VERSION 5.8 ;
BUSBITCHARS "[]" ;
DIVIDERCHAR "/" ;
UNITS
    DATABASE MICRONS 1000 ;
END UNITS

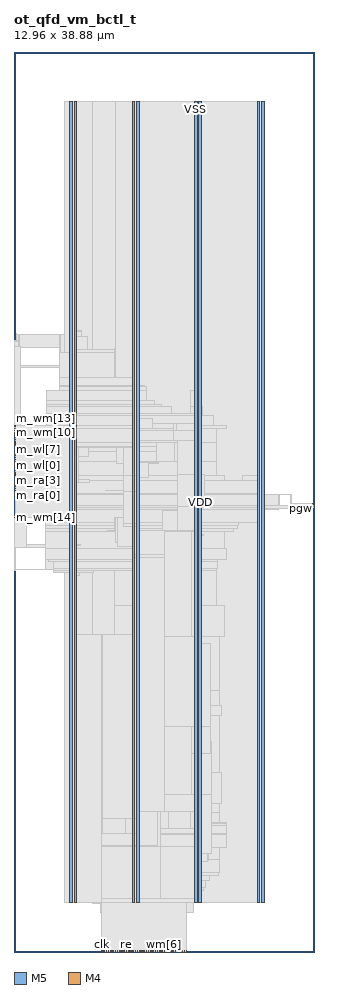
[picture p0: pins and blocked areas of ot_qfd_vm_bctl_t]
MACRO ot_qfd_vm_bctl_t
  FOREIGN ot_qfd_vm_bctl_t 0 0 ;
  CLASS BLOCK ;
  SIZE 12.96 BY 38.88 ;
  PIN clk
    DIRECTION INPUT ;
    USE SIGNAL ;
    PORT
      LAYER M5 ;
        RECT  3.792 0 3.816 0.084 ;
    END
  END clk
  PIN m_ra[0]
    DIRECTION OUTPUT ;
    USE SIGNAL ;
    PORT
      LAYER M4 ;
        RECT  0 19.728 0.084 19.752 ;
    END
  END m_ra[0]
  PIN m_ra[1]
    DIRECTION OUTPUT ;
    USE SIGNAL ;
    PORT
      LAYER M4 ;
        RECT  0 19.824 0.084 19.848 ;
    END
  END m_ra[1]
  PIN m_ra[2]
    DIRECTION OUTPUT ;
    USE SIGNAL ;
    PORT
      LAYER M4 ;
        RECT  0 19.92 0.084 19.944 ;
    END
  END m_ra[2]
  PIN m_ra[3]
    DIRECTION OUTPUT ;
    USE SIGNAL ;
    PORT
      LAYER M4 ;
        RECT  0 20.016 0.084 20.04 ;
    END
  END m_ra[3]
  PIN m_ra[4]
    DIRECTION OUTPUT ;
    USE SIGNAL ;
    PORT
      LAYER M4 ;
        RECT  0 20.112 0.084 20.136 ;
    END
  END m_ra[4]
  PIN m_ra[5]
    DIRECTION OUTPUT ;
    USE SIGNAL ;
    PORT
      LAYER M4 ;
        RECT  0 20.208 0.084 20.232 ;
    END
  END m_ra[5]
  PIN m_ra[6]
    DIRECTION OUTPUT ;
    USE SIGNAL ;
    PORT
      LAYER M4 ;
        RECT  0 20.304 0.084 20.328 ;
    END
  END m_ra[6]
  PIN m_ra[7]
    DIRECTION OUTPUT ;
    USE SIGNAL ;
    PORT
      LAYER M4 ;
        RECT  0 20.4 0.084 20.424 ;
    END
  END m_ra[7]
  PIN m_re
    DIRECTION OUTPUT ;
    USE SIGNAL ;
    PORT
      LAYER M4 ;
        RECT  0 20.496 0.084 20.52 ;
    END
  END m_re
  PIN m_we
    DIRECTION OUTPUT ;
    USE SIGNAL ;
    PORT
      LAYER M4 ;
        RECT  0 20.592 0.084 20.616 ;
    END
  END m_we
  PIN m_wl[0]
    DIRECTION OUTPUT ;
    USE SIGNAL ;
    PORT
      LAYER M4 ;
        RECT  0 20.688 0.084 20.712 ;
    END
  END m_wl[0]
  PIN m_wl[1]
    DIRECTION OUTPUT ;
    USE SIGNAL ;
    PORT
      LAYER M4 ;
        RECT  0 20.784 0.084 20.808 ;
    END
  END m_wl[1]
  PIN m_wl[2]
    DIRECTION OUTPUT ;
    USE SIGNAL ;
    PORT
      LAYER M4 ;
        RECT  0 20.88 0.084 20.904 ;
    END
  END m_wl[2]
  PIN m_wl[3]
    DIRECTION OUTPUT ;
    USE SIGNAL ;
    PORT
      LAYER M4 ;
        RECT  0 20.976 0.084 21 ;
    END
  END m_wl[3]
  PIN m_wl[4]
    DIRECTION OUTPUT ;
    USE SIGNAL ;
    PORT
      LAYER M4 ;
        RECT  0 21.072 0.084 21.096 ;
    END
  END m_wl[4]
  PIN m_wl[5]
    DIRECTION OUTPUT ;
    USE SIGNAL ;
    PORT
      LAYER M4 ;
        RECT  0 21.168 0.084 21.192 ;
    END
  END m_wl[5]
  PIN m_wl[6]
    DIRECTION OUTPUT ;
    USE SIGNAL ;
    PORT
      LAYER M4 ;
        RECT  0 21.264 0.084 21.288 ;
    END
  END m_wl[6]
  PIN m_wl[7]
    DIRECTION OUTPUT ;
    USE SIGNAL ;
    PORT
      LAYER M4 ;
        RECT  0 21.36 0.084 21.384 ;
    END
  END m_wl[7]
  PIN m_wm[0]
    DIRECTION OUTPUT ;
    USE SIGNAL ;
    PORT
      LAYER M4 ;
        RECT  0 21.456 0.084 21.48 ;
    END
  END m_wm[0]
  PIN m_wm[10]
    DIRECTION OUTPUT ;
    USE SIGNAL ;
    PORT
      LAYER M4 ;
        RECT  0 22.416 0.084 22.44 ;
    END
  END m_wm[10]
  PIN m_wm[11]
    DIRECTION OUTPUT ;
    USE SIGNAL ;
    PORT
      LAYER M4 ;
        RECT  0 22.512 0.084 22.536 ;
    END
  END m_wm[11]
  PIN m_wm[12]
    DIRECTION OUTPUT ;
    USE SIGNAL ;
    PORT
      LAYER M4 ;
        RECT  0 22.608 0.084 22.632 ;
    END
  END m_wm[12]
  PIN m_wm[13]
    DIRECTION OUTPUT ;
    USE SIGNAL ;
    PORT
      LAYER M4 ;
        RECT  0 22.704 0.084 22.728 ;
    END
  END m_wm[13]
  PIN m_wm[14]
    DIRECTION OUTPUT ;
    USE SIGNAL ;
    PORT
      LAYER M4 ;
        RECT  0 18.768 0.084 18.792 ;
    END
  END m_wm[14]
  PIN m_wm[15]
    DIRECTION OUTPUT ;
    USE SIGNAL ;
    PORT
      LAYER M4 ;
        RECT  0 18.864 0.084 18.888 ;
    END
  END m_wm[15]
  PIN m_wm[1]
    DIRECTION OUTPUT ;
    USE SIGNAL ;
    PORT
      LAYER M4 ;
        RECT  0 21.552 0.084 21.576 ;
    END
  END m_wm[1]
  PIN m_wm[2]
    DIRECTION OUTPUT ;
    USE SIGNAL ;
    PORT
      LAYER M4 ;
        RECT  0 21.648 0.084 21.672 ;
    END
  END m_wm[2]
  PIN m_wm[3]
    DIRECTION OUTPUT ;
    USE SIGNAL ;
    PORT
      LAYER M4 ;
        RECT  0 21.744 0.084 21.768 ;
    END
  END m_wm[3]
  PIN m_wm[4]
    DIRECTION OUTPUT ;
    USE SIGNAL ;
    PORT
      LAYER M4 ;
        RECT  0 21.84 0.084 21.864 ;
    END
  END m_wm[4]
  PIN m_wm[5]
    DIRECTION OUTPUT ;
    USE SIGNAL ;
    PORT
      LAYER M4 ;
        RECT  0 21.936 0.084 21.96 ;
    END
  END m_wm[5]
  PIN m_wm[6]
    DIRECTION OUTPUT ;
    USE SIGNAL ;
    PORT
      LAYER M4 ;
        RECT  0 22.032 0.084 22.056 ;
    END
  END m_wm[6]
  PIN m_wm[7]
    DIRECTION OUTPUT ;
    USE SIGNAL ;
    PORT
      LAYER M4 ;
        RECT  0 22.128 0.084 22.152 ;
    END
  END m_wm[7]
  PIN m_wm[8]
    DIRECTION OUTPUT ;
    USE SIGNAL ;
    PORT
      LAYER M4 ;
        RECT  0 22.224 0.084 22.248 ;
    END
  END m_wm[8]
  PIN m_wm[9]
    DIRECTION OUTPUT ;
    USE SIGNAL ;
    PORT
      LAYER M4 ;
        RECT  0 22.32 0.084 22.344 ;
    END
  END m_wm[9]
  PIN me_in
    DIRECTION INPUT ;
    USE SIGNAL ;
    PORT
      LAYER M5 ;
        RECT  3.888 0 3.912 0.084 ;
    END
  END me_in
  PIN pgw
    DIRECTION OUTPUT ;
    USE SIGNAL ;
    PORT
      LAYER M4 ;
        RECT  12.876 19.152 12.96 19.176 ;
    END
  END pgw
  PIN pop
    DIRECTION INPUT ;
    USE SIGNAL ;
    PORT
      LAYER M5 ;
        RECT  3.984 0 4.008 0.084 ;
    END
  END pop
  PIN ra[0]
    DIRECTION INPUT ;
    USE SIGNAL ;
    PORT
      LAYER M5 ;
        RECT  4.08 0 4.104 0.084 ;
    END
  END ra[0]
  PIN ra[1]
    DIRECTION INPUT ;
    USE SIGNAL ;
    PORT
      LAYER M5 ;
        RECT  4.176 0 4.2 0.084 ;
    END
  END ra[1]
  PIN ra[2]
    DIRECTION INPUT ;
    USE SIGNAL ;
    PORT
      LAYER M5 ;
        RECT  4.272 0 4.296 0.084 ;
    END
  END ra[2]
  PIN ra[3]
    DIRECTION INPUT ;
    USE SIGNAL ;
    PORT
      LAYER M5 ;
        RECT  4.368 0 4.392 0.084 ;
    END
  END ra[3]
  PIN ra[4]
    DIRECTION INPUT ;
    USE SIGNAL ;
    PORT
      LAYER M5 ;
        RECT  4.464 0 4.488 0.084 ;
    END
  END ra[4]
  PIN ra[5]
    DIRECTION INPUT ;
    USE SIGNAL ;
    PORT
      LAYER M5 ;
        RECT  4.56 0 4.584 0.084 ;
    END
  END ra[5]
  PIN ra[6]
    DIRECTION INPUT ;
    USE SIGNAL ;
    PORT
      LAYER M5 ;
        RECT  4.656 0 4.68 0.084 ;
    END
  END ra[6]
  PIN ra[7]
    DIRECTION INPUT ;
    USE SIGNAL ;
    PORT
      LAYER M5 ;
        RECT  4.752 0 4.776 0.084 ;
    END
  END ra[7]
  PIN re
    DIRECTION INPUT ;
    USE SIGNAL ;
    PORT
      LAYER M5 ;
        RECT  4.848 0 4.872 0.084 ;
    END
  END re
  PIN rst_n
    DIRECTION INPUT ;
    USE SIGNAL ;
    PORT
      LAYER M5 ;
        RECT  4.944 0 4.968 0.084 ;
    END
  END rst_n
  PIN rtg
    DIRECTION OUTPUT ;
    USE SIGNAL ;
    PORT
      LAYER M4 ;
        RECT  12.876 19.248 12.96 19.272 ;
    END
  END rtg
  PIN we
    DIRECTION INPUT ;
    USE SIGNAL ;
    PORT
      LAYER M5 ;
        RECT  5.04 0 5.064 0.084 ;
    END
  END we
  PIN wl[0]
    DIRECTION INPUT ;
    USE SIGNAL ;
    PORT
      LAYER M5 ;
        RECT  5.136 0 5.16 0.084 ;
    END
  END wl[0]
  PIN wl[1]
    DIRECTION INPUT ;
    USE SIGNAL ;
    PORT
      LAYER M5 ;
        RECT  5.232 0 5.256 0.084 ;
    END
  END wl[1]
  PIN wl[2]
    DIRECTION INPUT ;
    USE SIGNAL ;
    PORT
      LAYER M5 ;
        RECT  5.328 0 5.352 0.084 ;
    END
  END wl[2]
  PIN wl[3]
    DIRECTION INPUT ;
    USE SIGNAL ;
    PORT
      LAYER M5 ;
        RECT  5.424 0 5.448 0.084 ;
    END
  END wl[3]
  PIN wl[4]
    DIRECTION INPUT ;
    USE SIGNAL ;
    PORT
      LAYER M5 ;
        RECT  5.52 0 5.544 0.084 ;
    END
  END wl[4]
  PIN wl[5]
    DIRECTION INPUT ;
    USE SIGNAL ;
    PORT
      LAYER M5 ;
        RECT  5.616 0 5.64 0.084 ;
    END
  END wl[5]
  PIN wl[6]
    DIRECTION INPUT ;
    USE SIGNAL ;
    PORT
      LAYER M5 ;
        RECT  5.712 0 5.736 0.084 ;
    END
  END wl[6]
  PIN wl[7]
    DIRECTION INPUT ;
    USE SIGNAL ;
    PORT
      LAYER M5 ;
        RECT  5.808 0 5.832 0.084 ;
    END
  END wl[7]
  PIN wm[0]
    DIRECTION INPUT ;
    USE SIGNAL ;
    PORT
      LAYER M5 ;
        RECT  5.904 0 5.928 0.084 ;
    END
  END wm[0]
  PIN wm[10]
    DIRECTION INPUT ;
    USE SIGNAL ;
    PORT
      LAYER M5 ;
        RECT  6.864 0 6.888 0.084 ;
    END
  END wm[10]
  PIN wm[11]
    DIRECTION INPUT ;
    USE SIGNAL ;
    PORT
      LAYER M5 ;
        RECT  6.96 0 6.984 0.084 ;
    END
  END wm[11]
  PIN wm[12]
    DIRECTION INPUT ;
    USE SIGNAL ;
    PORT
      LAYER M5 ;
        RECT  7.056 0 7.08 0.084 ;
    END
  END wm[12]
  PIN wm[13]
    DIRECTION INPUT ;
    USE SIGNAL ;
    PORT
      LAYER M5 ;
        RECT  7.152 0 7.176 0.084 ;
    END
  END wm[13]
  PIN wm[14]
    DIRECTION INPUT ;
    USE SIGNAL ;
    PORT
      LAYER M5 ;
        RECT  7.248 0 7.272 0.084 ;
    END
  END wm[14]
  PIN wm[15]
    DIRECTION INPUT ;
    USE SIGNAL ;
    PORT
      LAYER M5 ;
        RECT  7.344 0 7.368 0.084 ;
    END
  END wm[15]
  PIN wm[1]
    DIRECTION INPUT ;
    USE SIGNAL ;
    PORT
      LAYER M5 ;
        RECT  6 0 6.024 0.084 ;
    END
  END wm[1]
  PIN wm[2]
    DIRECTION INPUT ;
    USE SIGNAL ;
    PORT
      LAYER M5 ;
        RECT  6.096 0 6.12 0.084 ;
    END
  END wm[2]
  PIN wm[3]
    DIRECTION INPUT ;
    USE SIGNAL ;
    PORT
      LAYER M5 ;
        RECT  6.192 0 6.216 0.084 ;
    END
  END wm[3]
  PIN wm[4]
    DIRECTION INPUT ;
    USE SIGNAL ;
    PORT
      LAYER M5 ;
        RECT  6.288 0 6.312 0.084 ;
    END
  END wm[4]
  PIN wm[5]
    DIRECTION INPUT ;
    USE SIGNAL ;
    PORT
      LAYER M5 ;
        RECT  6.384 0 6.408 0.084 ;
    END
  END wm[5]
  PIN wm[6]
    DIRECTION INPUT ;
    USE SIGNAL ;
    PORT
      LAYER M5 ;
        RECT  6.48 0 6.504 0.084 ;
    END
  END wm[6]
  PIN wm[7]
    DIRECTION INPUT ;
    USE SIGNAL ;
    PORT
      LAYER M5 ;
        RECT  6.576 0 6.6 0.084 ;
    END
  END wm[7]
  PIN wm[8]
    DIRECTION INPUT ;
    USE SIGNAL ;
    PORT
      LAYER M5 ;
        RECT  6.672 0 6.696 0.084 ;
    END
  END wm[8]
  PIN wm[9]
    DIRECTION INPUT ;
    USE SIGNAL ;
    PORT
      LAYER M5 ;
        RECT  6.768 0 6.792 0.084 ;
    END
  END wm[9]
  PIN xg
    DIRECTION OUTPUT ;
    USE SIGNAL ;
    PORT
      LAYER M4 ;
        RECT  12.876 19.344 12.96 19.368 ;
    END
  END xg
  PIN xv
    DIRECTION INPUT ;
    USE SIGNAL ;
    PORT
      LAYER M5 ;
        RECT  7.44 0 7.464 0.084 ;
    END
  END xv
  PIN VDD
    DIRECTION INOUT ;
    USE POWER ;
    PORT
      LAYER M5 ;
        RECT  10.692 2.151 10.812 36.729 ;
        RECT  7.992 2.151 8.112 36.729 ;
        RECT  5.292 2.151 5.412 36.729 ;
        RECT  2.592 2.151 2.712 36.729 ;
    END
  END VDD
  PIN VSS
    DIRECTION INOUT ;
    USE GROUND ;
    PORT
      LAYER M5 ;
        RECT  10.5 2.137 10.62 36.743 ;
        RECT  7.8 2.137 7.92 36.743 ;
        RECT  5.1 2.137 5.22 36.743 ;
        RECT  2.4 2.137 2.52 36.743 ;
    END
  END VSS
  # OT_OBS_CLOSED layer=M5 d_um=1.536 added=14
  OBS
    LAYER RVTN ;
     RECT  2.16 2.16 10.8 2.295 ;
     RECT  2.16 2.565 10.8 2.835 ;
     RECT  2.16 3.105 10.8 3.375 ;
     RECT  2.16 3.645 10.8 3.915 ;
     RECT  2.16 4.185 10.8 4.455 ;
     RECT  2.16 4.725 10.8 4.995 ;
     RECT  2.16 5.265 10.8 5.535 ;
     RECT  2.16 5.805 10.8 6.075 ;
     RECT  2.16 6.345 10.8 6.615 ;
     RECT  2.16 6.885 10.8 7.155 ;
     RECT  2.16 7.425 10.8 7.695 ;
     RECT  2.16 7.965 10.8 8.235 ;
     RECT  2.16 8.505 10.8 8.775 ;
     RECT  2.16 9.045 10.8 9.315 ;
     RECT  2.16 9.585 10.8 9.855 ;
     RECT  2.16 10.125 10.8 10.395 ;
     RECT  2.16 10.665 10.8 10.935 ;
     RECT  2.16 11.205 10.8 11.475 ;
     RECT  2.16 11.745 10.8 12.015 ;
     RECT  2.16 12.285 10.8 12.555 ;
     RECT  2.16 12.825 10.8 13.095 ;
     RECT  2.16 13.365 10.8 13.635 ;
     RECT  2.16 13.905 10.8 14.175 ;
     RECT  2.16 14.445 10.8 14.715 ;
     RECT  2.16 14.985 10.8 15.255 ;
     RECT  2.16 15.525 10.8 15.795 ;
     RECT  2.16 16.065 10.8 16.335 ;
     RECT  2.16 16.605 10.8 16.875 ;
     RECT  2.16 17.145 10.8 17.415 ;
     RECT  2.16 17.685 10.8 17.955 ;
     RECT  2.16 18.225 10.8 18.495 ;
     RECT  2.16 18.765 10.8 19.035 ;
     RECT  2.16 19.305 10.8 19.575 ;
     RECT  2.16 19.845 10.8 20.115 ;
     RECT  2.16 20.385 10.8 20.655 ;
     RECT  2.16 20.925 10.8 21.195 ;
     RECT  2.16 21.465 10.8 21.735 ;
     RECT  2.16 22.005 10.8 22.275 ;
     RECT  2.16 22.545 10.8 22.815 ;
     RECT  2.16 23.085 10.8 23.355 ;
     RECT  2.16 23.625 10.8 23.895 ;
     RECT  2.16 24.165 10.8 24.435 ;
     RECT  2.16 24.705 10.8 24.975 ;
     RECT  2.16 25.245 10.8 25.515 ;
     RECT  2.16 25.785 10.8 26.055 ;
     RECT  2.16 26.325 10.8 26.595 ;
     RECT  2.16 26.865 10.8 27.135 ;
     RECT  2.16 27.405 10.8 27.675 ;
     RECT  2.16 27.945 10.8 28.215 ;
     RECT  2.16 28.485 10.8 28.755 ;
     RECT  2.16 29.025 10.8 29.295 ;
     RECT  2.16 29.565 10.8 29.835 ;
     RECT  2.16 30.105 10.8 30.375 ;
     RECT  2.16 30.645 10.8 30.915 ;
     RECT  2.16 31.185 10.8 31.455 ;
     RECT  2.16 31.725 10.8 31.995 ;
     RECT  2.16 32.265 10.8 32.535 ;
     RECT  2.16 32.805 10.8 33.075 ;
     RECT  2.16 33.345 10.8 33.615 ;
     RECT  2.16 33.885 10.8 34.155 ;
     RECT  2.16 34.425 10.8 34.695 ;
     RECT  2.16 34.965 10.8 35.235 ;
     RECT  2.16 35.505 10.8 35.775 ;
     RECT  2.16 36.045 10.8 36.315 ;
     RECT  2.16 36.585 10.8 36.72 ;
    LAYER RVTP ;
     RECT  2.16 2.295 10.8 2.565 ;
     RECT  2.16 2.835 10.8 3.105 ;
     RECT  2.16 3.375 10.8 3.645 ;
     RECT  2.16 3.915 10.8 4.185 ;
     RECT  2.16 4.455 10.8 4.725 ;
     RECT  2.16 4.995 10.8 5.265 ;
     RECT  2.16 5.535 10.8 5.805 ;
     RECT  2.16 6.075 10.8 6.345 ;
     RECT  2.16 6.615 10.8 6.885 ;
     RECT  2.16 7.155 10.8 7.425 ;
     RECT  2.16 7.695 10.8 7.965 ;
     RECT  2.16 8.235 10.8 8.505 ;
     RECT  2.16 8.775 10.8 9.045 ;
     RECT  2.16 9.315 10.8 9.585 ;
     RECT  2.16 9.855 10.8 10.125 ;
     RECT  2.16 10.395 10.8 10.665 ;
     RECT  2.16 10.935 10.8 11.205 ;
     RECT  2.16 11.475 10.8 11.745 ;
     RECT  2.16 12.015 10.8 12.285 ;
     RECT  2.16 12.555 10.8 12.825 ;
     RECT  2.16 13.095 10.8 13.365 ;
     RECT  2.16 13.635 10.8 13.905 ;
     RECT  2.16 14.175 10.8 14.445 ;
     RECT  2.16 14.715 10.8 14.985 ;
     RECT  2.16 15.255 10.8 15.525 ;
     RECT  2.16 15.795 10.8 16.065 ;
     RECT  2.16 16.335 10.8 16.605 ;
     RECT  2.16 16.875 10.8 17.145 ;
     RECT  2.16 17.415 10.8 17.685 ;
     RECT  2.16 17.955 10.8 18.225 ;
     RECT  2.16 18.495 10.8 18.765 ;
     RECT  2.16 19.035 10.8 19.305 ;
     RECT  2.16 19.575 10.8 19.845 ;
     RECT  2.16 20.115 10.8 20.385 ;
     RECT  2.16 20.655 10.8 20.925 ;
     RECT  2.16 21.195 10.8 21.465 ;
     RECT  2.16 21.735 10.8 22.005 ;
     RECT  2.16 22.275 10.8 22.545 ;
     RECT  2.16 22.815 10.8 23.085 ;
     RECT  2.16 23.355 10.8 23.625 ;
     RECT  2.16 23.895 10.8 24.165 ;
     RECT  2.16 24.435 10.8 24.705 ;
     RECT  2.16 24.975 10.8 25.245 ;
     RECT  2.16 25.515 10.8 25.785 ;
     RECT  2.16 26.055 10.8 26.325 ;
     RECT  2.16 26.595 10.8 26.865 ;
     RECT  2.16 27.135 10.8 27.405 ;
     RECT  2.16 27.675 10.8 27.945 ;
     RECT  2.16 28.215 10.8 28.485 ;
     RECT  2.16 28.755 10.8 29.025 ;
     RECT  2.16 29.295 10.8 29.565 ;
     RECT  2.16 29.835 10.8 30.105 ;
     RECT  2.16 30.375 10.8 30.645 ;
     RECT  2.16 30.915 10.8 31.185 ;
     RECT  2.16 31.455 10.8 31.725 ;
     RECT  2.16 31.995 10.8 32.265 ;
     RECT  2.16 32.535 10.8 32.805 ;
     RECT  2.16 33.075 10.8 33.345 ;
     RECT  2.16 33.615 10.8 33.885 ;
     RECT  2.16 34.155 10.8 34.425 ;
     RECT  2.16 34.695 10.8 34.965 ;
     RECT  2.16 35.235 10.8 35.505 ;
     RECT  2.16 35.775 10.8 36.045 ;
     RECT  2.16 36.315 10.8 36.585 ;
    LAYER M1 ;
     RECT  2.16 2.151 10.8 36.729 ;
    LAYER M2 ;
     RECT  0.031 18.891 0.103 18.909 ;
     RECT  0.031 26.406 0.103 26.424 ;
     RECT  0.031 22.356 0.131 22.374 ;
     RECT  0.103 18.81 0.139 18.909 ;
     RECT  0.067 25.326 0.139 25.344 ;
     RECT  0.067 21.591 0.167 21.609 ;
     RECT  0.103 26.406 0.175 26.694 ;
     RECT  0.139 18.81 0.211 19.332 ;
     RECT  0.175 26.334 0.247 26.694 ;
     RECT  0.103 17.586 0.535 17.604 ;
     RECT  0.211 18.774 0.535 19.332 ;
     RECT  0.031 16.506 1.363 16.524 ;
     RECT  0.535 17.46 1.363 17.604 ;
     RECT  0.535 18.774 1.435 19.602 ;
     RECT  1.363 16.506 1.723 17.604 ;
     RECT  0.139 25.254 1.975 25.344 ;
     RECT  0.247 26.136 1.975 26.694 ;
     RECT  1.399 24.246 2.011 24.264 ;
     RECT  1.975 25.254 2.011 26.694 ;
     RECT  1.723 16.416 2.16 17.604 ;
     RECT  1.435 18.666 2.16 19.602 ;
     RECT  2.011 24.246 2.16 26.694 ;
     RECT  2.16 2.151 3.379 36.729 ;
     RECT  3.379 2.106 4.379 36.729 ;
     RECT  4.379 2.151 10.8 36.729 ;
     RECT  10.8 2.421 10.812 36.459 ;
     RECT  10.812 19.116 11.435 19.764 ;
     RECT  11.435 19.206 11.471 19.764 ;
     RECT  11.471 19.746 11.975 19.764 ;
    LAYER M3 ;
     RECT  4.896 0.523 4.914 0.571 ;
     RECT  4.356 0.571 4.914 1.723 ;
     RECT  5.796 0.091 5.814 1.723 ;
     RECT  6.948 1.099 6.966 1.723 ;
     RECT  3.744 1.723 7.722 2.101 ;
     RECT  3.384 2.101 7.722 2.143 ;
     RECT  3.384 2.143 7.905 2.255 ;
     RECT  3.6 2.255 7.905 2.263 ;
     RECT  2.415 2.143 2.505 2.413 ;
     RECT  3.6 2.263 7.974 2.413 ;
     RECT  10.515 2.143 10.605 2.413 ;
     RECT  3.6 2.413 8.097 2.489 ;
     RECT  3.78 2.489 8.097 2.641 ;
     RECT  3.78 2.641 8.19 2.803 ;
     RECT  3.78 2.803 8.262 3.109 ;
     RECT  3.78 3.109 8.442 3.307 ;
     RECT  3.78 3.307 8.838 3.451 ;
     RECT  3.456 3.451 8.874 4.013 ;
     RECT  3.816 4.013 8.874 4.531 ;
     RECT  3.816 4.531 9.198 5.071 ;
     RECT  3.564 5.071 9.198 5.117 ;
     RECT  3.816 5.117 9.198 5.459 ;
     RECT  4.068 5.459 9.198 5.531 ;
     RECT  4.356 5.531 9.198 5.603 ;
     RECT  4.356 5.603 8.874 6.035 ;
     RECT  4.392 6.035 8.874 6.421 ;
     RECT  4.392 6.421 8.946 7.763 ;
     RECT  4.392 7.763 8.874 10.201 ;
     RECT  4.392 10.201 8.946 10.661 ;
     RECT  4.392 10.661 8.874 11.281 ;
     RECT  4.356 11.281 8.874 13.639 ;
     RECT  4.356 13.639 9.09 14.981 ;
     RECT  2.415 2.413 2.697 16.267 ;
     RECT  2.415 16.267 2.826 16.411 ;
     RECT  1.728 16.411 3.438 16.501 ;
     RECT  4.356 14.981 8.766 16.501 ;
     RECT  1.728 16.501 8.766 16.573 ;
     RECT  1.728 16.573 8.802 16.879 ;
     RECT  1.476 16.879 8.802 16.951 ;
     RECT  1.368 16.951 9.198 17.411 ;
     RECT  0.036 16.501 0.054 17.455 ;
     RECT  1.368 17.411 9.09 18.157 ;
     RECT  1.368 18.157 9.486 18.301 ;
     RECT  1.368 18.301 9.666 18.427 ;
     RECT  1.368 18.427 9.702 18.571 ;
     RECT  10.515 2.413 10.797 18.571 ;
     RECT  0.036 17.455 0.558 18.914 ;
     RECT  1.368 18.571 10.797 19.111 ;
     RECT  1.368 19.111 11.43 19.201 ;
     RECT  1.368 19.201 11.466 19.277 ;
     RECT  1.368 19.277 10.797 19.757 ;
     RECT  11.952 19.339 11.97 19.769 ;
     RECT  2.304 19.757 10.797 19.805 ;
     RECT  1.368 19.757 1.494 19.949 ;
     RECT  0.108 18.914 0.558 20.045 ;
     RECT  1.44 19.949 1.494 20.141 ;
     RECT  2.376 19.805 10.797 20.381 ;
     RECT  2.376 20.381 9.09 20.579 ;
     RECT  9.864 20.381 10.797 20.579 ;
     RECT  2.376 20.579 8.766 20.587 ;
     RECT  1.44 20.141 1.458 20.717 ;
     RECT  0.144 20.045 0.558 20.909 ;
     RECT  2.304 20.587 8.766 21.191 ;
     RECT  0.144 20.909 0.342 21.485 ;
     RECT  0.144 21.485 0.162 21.586 ;
     RECT  2.304 21.191 6.174 21.643 ;
     RECT  2.016 21.643 6.174 21.835 ;
     RECT  1.404 21.835 6.174 22.009 ;
     RECT  6.948 21.191 8.766 22.009 ;
     RECT  0.072 21.586 0.162 22.219 ;
     RECT  0.072 22.219 0.198 22.315 ;
     RECT  0.072 22.315 0.27 22.351 ;
     RECT  1.404 22.009 8.766 22.621 ;
     RECT  1.404 22.621 9.162 22.739 ;
     RECT  1.404 22.739 8.622 23.189 ;
     RECT  1.404 23.189 8.154 23.279 ;
     RECT  1.404 23.279 6.822 23.585 ;
     RECT  7.632 23.279 8.154 23.585 ;
     RECT  1.404 23.585 6.354 23.657 ;
     RECT  1.404 23.657 6.066 23.819 ;
     RECT  1.404 23.819 5.706 24.269 ;
     RECT  7.632 23.585 8.097 24.269 ;
     RECT  1.98 24.269 5.706 24.431 ;
     RECT  1.98 24.431 5.634 24.467 ;
     RECT  1.98 24.467 5.397 24.809 ;
     RECT  1.98 24.809 4.338 25.889 ;
     RECT  2.415 25.889 4.338 26.015 ;
     RECT  4.32 26.015 4.338 26.087 ;
     RECT  0.036 22.351 0.27 26.159 ;
     RECT  0.036 26.159 0.198 26.357 ;
     RECT  0.036 26.357 0.126 26.429 ;
     RECT  2.415 26.015 3.186 26.591 ;
     RECT  0.108 26.429 0.126 26.699 ;
     RECT  2.415 26.591 2.934 26.789 ;
     RECT  2.415 26.789 2.898 26.861 ;
     RECT  2.415 26.861 2.697 36.467 ;
     RECT  5.115 24.809 5.397 36.467 ;
     RECT  7.815 24.269 8.097 36.467 ;
     RECT  10.515 20.579 10.797 36.467 ;
     RECT  2.415 36.467 2.505 36.737 ;
     RECT  5.115 36.467 5.205 36.737 ;
     RECT  7.815 36.467 7.905 36.737 ;
     RECT  10.515 36.467 10.605 36.737 ;
    LAYER M4 ;
     RECT  0.06 18.768 2.408 22.728 ;
     RECT  2.408 2.148 2.512 36.732 ;
     RECT  2.512 2.418 2.704 36.462 ;
     RECT  2.704 20.304 2.765 21.816 ;
     RECT  2.704 17.568 2.873 17.592 ;
     RECT  2.765 21.408 3.197 21.816 ;
     RECT  2.765 20.304 3.269 20.424 ;
     RECT  2.704 3.984 3.841 4.008 ;
     RECT  3.733 1.728 3.985 1.752 ;
     RECT  3.841 3.936 4.057 4.008 ;
     RECT  3.985 1.728 4.114 1.8 ;
     RECT  4.057 18.192 4.345 18.216 ;
     RECT  4.345 18.192 4.381 18.792 ;
     RECT  3.197 21.792 4.417 21.816 ;
     RECT  4.381 17.712 4.489 18.792 ;
     RECT  2.704 5.088 4.669 5.112 ;
     RECT  4.114 1.728 4.7 1.848 ;
     RECT  4.453 2.88 4.7 2.904 ;
     RECT  4.345 0.576 4.717 0.6 ;
     RECT  3.949 19.92 4.741 19.944 ;
     RECT  4.417 21.12 4.741 21.816 ;
     RECT  4.057 3.936 4.777 4.056 ;
     RECT  4.669 5.088 4.777 5.496 ;
     RECT  4.777 3.936 4.789 5.496 ;
     RECT  4.789 3.936 4.993 5.736 ;
     RECT  4.7 1.728 5.108 2.904 ;
     RECT  4.993 3.936 5.108 6.264 ;
     RECT  3.781 13.68 5.108 13.704 ;
     RECT  4.489 17.52 5.108 18.792 ;
     RECT  4.741 19.92 5.108 21.816 ;
     RECT  5.108 1.728 5.212 36.732 ;
     RECT  5.212 1.728 5.404 36.462 ;
     RECT  4.885 0.144 5.459 0.552 ;
     RECT  5.404 17.04 5.581 18.216 ;
     RECT  5.404 11.232 5.753 11.256 ;
     RECT  5.404 20.496 5.789 21.144 ;
     RECT  5.701 0.096 5.825 0.12 ;
     RECT  5.404 22.608 5.969 23.064 ;
     RECT  5.581 17.616 6.005 18.216 ;
     RECT  5.404 13.68 6.257 13.704 ;
     RECT  5.789 21.12 6.257 21.144 ;
     RECT  5.404 3.936 6.323 6.12 ;
     RECT  6.005 18.192 6.397 18.216 ;
     RECT  6.428 13.968 6.515 13.992 ;
     RECT  6.323 5.328 6.685 6.12 ;
     RECT  5.969 22.608 6.901 22.824 ;
     RECT  5.404 1.728 6.937 2.28 ;
     RECT  6.397 18.192 7.261 19.08 ;
     RECT  6.937 1.104 7.283 2.28 ;
     RECT  6.829 3.84 7.549 3.864 ;
     RECT  6.685 5.328 7.628 6.84 ;
     RECT  7.261 18.192 7.669 19.272 ;
     RECT  7.283 1.728 7.733 2.28 ;
     RECT  7.733 2.148 7.808 2.28 ;
     RECT  7.549 3.84 7.808 4.152 ;
     RECT  7.628 5.328 7.808 7.272 ;
     RECT  7.657 9.696 7.808 9.72 ;
     RECT  7.669 13.632 7.808 13.656 ;
     RECT  7.669 16.896 7.808 16.92 ;
     RECT  7.669 18 7.808 19.272 ;
     RECT  7.801 20.592 7.808 20.616 ;
     RECT  6.901 22.128 7.808 22.824 ;
     RECT  7.808 2.148 7.912 36.732 ;
     RECT  7.912 2.418 8.104 36.462 ;
     RECT  8.104 18 8.165 18.024 ;
     RECT  8.104 5.712 8.201 6.84 ;
     RECT  8.104 19.248 8.243 20.616 ;
     RECT  8.243 19.632 8.284 19.656 ;
     RECT  8.104 3.936 8.387 4.296 ;
     RECT  8.201 5.712 8.425 5.736 ;
     RECT  8.104 13.296 8.483 13.32 ;
     RECT  8.104 8.544 8.525 9.096 ;
     RECT  8.387 4.272 8.531 4.296 ;
     RECT  8.525 8.544 8.531 8.568 ;
     RECT  10.508 2.148 10.612 36.732 ;
     RECT  10.612 2.418 10.804 36.462 ;
     RECT  10.804 19.152 11.941 19.272 ;
     RECT  11.941 19.152 12.924 19.368 ;
    LAYER M5 ;
     RECT  3.792 0.016 7.464 2.137 ;
     RECT  2.4 2.137 2.52 2.151 ;
     RECT  3.792 2.137 7.92 2.151 ;
     RECT  10.5 2.137 10.62 2.151 ;
     RECT  3.792 2.151 8.112 2.291 ;
     RECT  7.8 2.291 8.112 3.925 ;
     RECT  7.8 3.925 8.376 4.261 ;
     RECT  3.792 2.291 6.312 4.547 ;
     RECT  3.792 4.547 6.216 4.595 ;
     RECT  3.792 4.595 5.412 5.123 ;
     RECT  4.8 5.123 5.412 5.747 ;
     RECT  7.8 4.261 8.52 6.805 ;
     RECT  7.68 6.805 8.52 8.579 ;
     RECT  7.68 8.579 8.472 9.731 ;
     RECT  7.8 9.731 8.472 13.331 ;
     RECT  7.8 13.331 8.112 13.621 ;
     RECT  3.792 5.123 3.816 13.715 ;
     RECT  5.1 5.747 5.412 17.029 ;
     RECT  6.48 6.085 6.504 17.029 ;
     RECT  5.1 17.029 6.504 17.171 ;
     RECT  6.48 17.171 6.504 18.181 ;
     RECT  7.68 13.621 8.112 18.181 ;
     RECT  6.48 18.181 8.112 18.227 ;
     RECT  5.1 17.171 5.412 18.373 ;
     RECT  4.752 18.373 5.412 18.515 ;
     RECT  7.056 18.227 8.112 19.237 ;
     RECT  5.1 18.515 5.412 19.909 ;
     RECT  4.752 19.909 5.412 20.579 ;
     RECT  7.056 19.237 8.232 20.627 ;
     RECT  7.056 20.627 8.112 22.117 ;
     RECT  6.912 22.117 8.112 22.547 ;
     RECT  7.008 22.547 8.112 22.835 ;
     RECT  2.4 2.151 2.712 36.729 ;
     RECT  5.1 20.579 5.412 36.729 ;
     RECT  7.8 22.835 8.112 36.729 ;
     RECT  10.5 2.151 10.812 36.729 ;
     RECT  2.4 36.729 2.52 36.743 ;
     RECT  5.1 36.729 5.22 36.743 ;
     RECT  7.8 36.729 7.92 36.743 ;
     RECT  10.5 36.729 10.62 36.743 ;
     RECT  2.52 2.137 3.792 2.151 ;
     RECT  2.712 2.151 3.792 13.715 ;
     RECT  6.312 2.291 7.8 4.547 ;
     RECT  5.412 4.595 6.216 6.085 ;
     RECT  3.816 5.123 4.8 5.747 ;
     RECT  3.816 5.747 5.1 13.715 ;
     RECT  5.412 6.085 6.48 17.029 ;
     RECT  6.504 6.085 7.8 6.805 ;
     RECT  6.504 6.805 7.68 9.731 ;
     RECT  6.504 9.731 7.8 13.621 ;
     RECT  6.504 13.621 7.68 18.181 ;
     RECT  5.412 17.171 6.48 18.227 ;
     RECT  4.752 18.515 5.1 19.909 ;
     RECT  5.412 22.117 6.912 22.547 ;
  END
END ot_qfd_vm_bctl_t
END LIBRARY
